(* Logix 5000 project; controller Example_PLC vendor 1 type 14 code 77 rev 19.11; software revision 19.01; part 3 of 6 *)
(* tags used below, declared in another part *)
   ENABLE : BOOL;
(* AKD_Jog, continued *)

ROUTINE Prescan   (* ladder *)
// Prescan
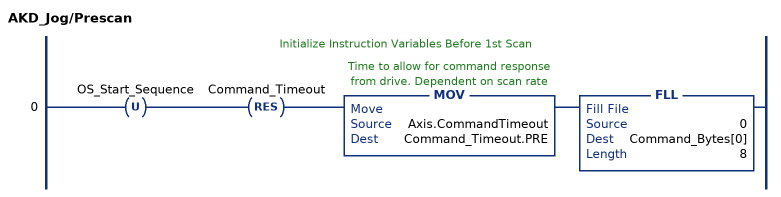
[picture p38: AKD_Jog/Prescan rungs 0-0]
   // Initialize Instruction Variables Before 1st Scan
   0: OTU(OS_Start_Sequence)RES(Command_Timeout)MOV(Axis.CommandTimeout,Command_Timeout.PRE)FLL(0,Command_Bytes[0],8);
END_ROUTINE
END_ADD_ON_INSTRUCTION

ADD_ON_INSTRUCTION AKD_Move   (* revision 3.1, ExecutePrescan, ExecuteEnableInFalse *)
// Motion Axis Move - Position Move
// Revision note:
// Don't error if Command_Timeout preset is 0
VAR_IN_OUT
   Axis : AKD_Axis; {required}
END_VAR
VAR_INPUT
   Move_Type : SINT; {required}   // Move Type (0=Absolute, 1=Incremental)
   Accel : DINT; {required}   // Acceleration
   Decel : DINT; {required}   // Deceleration
   Speed : DINT; {required}   // Move Speed
   Position : DINT; {required}   // Target Position
END_VAR
VAR_OUTPUT
   DN : BOOL; {access Read Only, visible}   // Command Successfully Initiated
   ER : BOOL; {access Read Only, visible}   // Error
   IP : BOOL; {access Read Only, visible}   // Command in Process
   PC : BOOL; {access Read Only, visible}   // Command Process Complete
END_VAR
VAR
   Step : SINT;   // Sequence Step Number
   Command_Axis_Number : SINT;
   Response_Axis_Number : SINT;
   Set_Accel : AKD_Set_Accel;
   Set_Decel : AKD_Set_Decel;
   Set_Velocity : AKD_Set_Velocity;
   OS_Start_Sequence : BOOL;
   Set_Position : AKD_Set_Position;
   Command_Timeout : TIMER := (PRE := 200);
   Command_Bytes : SINT[64];
   ErrorData : SINT[8];
END_VAR

ROUTINE EnableInFalse   (* ladder *)
// EnableIn_False
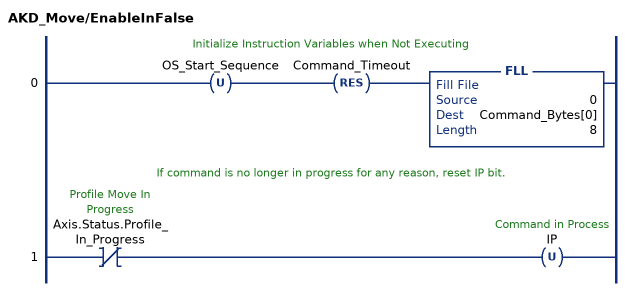
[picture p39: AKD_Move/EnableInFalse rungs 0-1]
   // Initialize Instruction Variables when Not Executing
   0: OTU(OS_Start_Sequence)RES(Command_Timeout)FLL(0,Command_Bytes[0],8);
   // If command is no longer in progress for any reason, reset IP bit.
   1: XIO(Axis.Status.Profile_In_Progress)OTU(IP);
END_ROUTINE

ROUTINE Logic   (* ladder *)
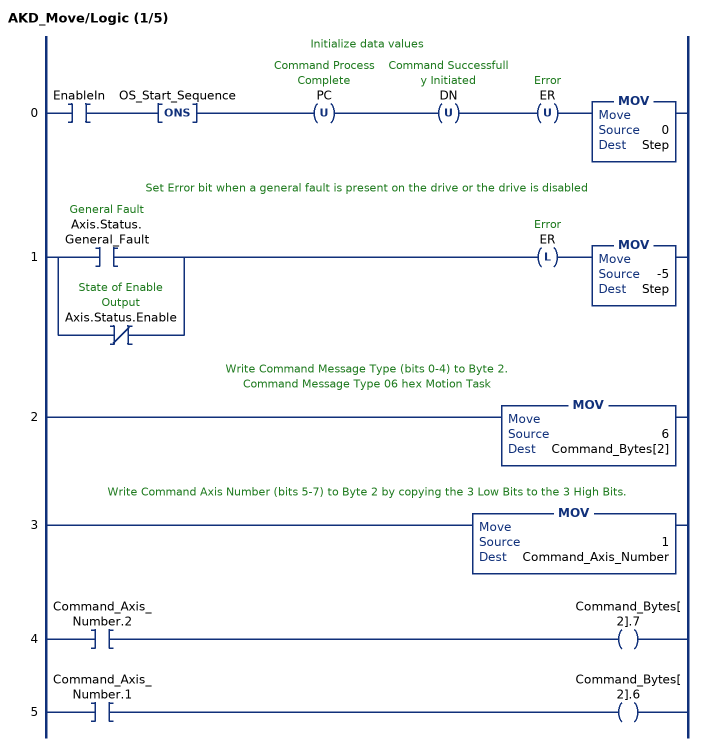
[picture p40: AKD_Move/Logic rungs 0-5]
   // Initialize data values
   0: XIC(EnableIn)ONS(OS_Start_Sequence)OTU(PC)OTU(DN)OTU(ER)MOV(0,Step);
   // Set Error bit when a general fault is present on the drive or the drive is disabled
   1: [XIC(Axis.Status.General_Fault) ,XIO(Axis.Status.Enable) ]OTL(ER)MOV(-5,Step);
   // Write Command Message Type (bits 0-4) to Byte 2.
   // Command Message Type 06 hex Motion Task
   2: MOV(6,Command_Bytes[2]);
   // Write Command Axis Number (bits 5-7) to Byte 2 by copying the 3 Low Bits to the 3 High Bits.
   3: MOV(1,Command_Axis_Number);
   4: XIC(Command_Axis_Number.2)OTE(Command_Bytes[2].7);
   5: XIC(Command_Axis_Number.1)OTE(Command_Bytes[2].6);
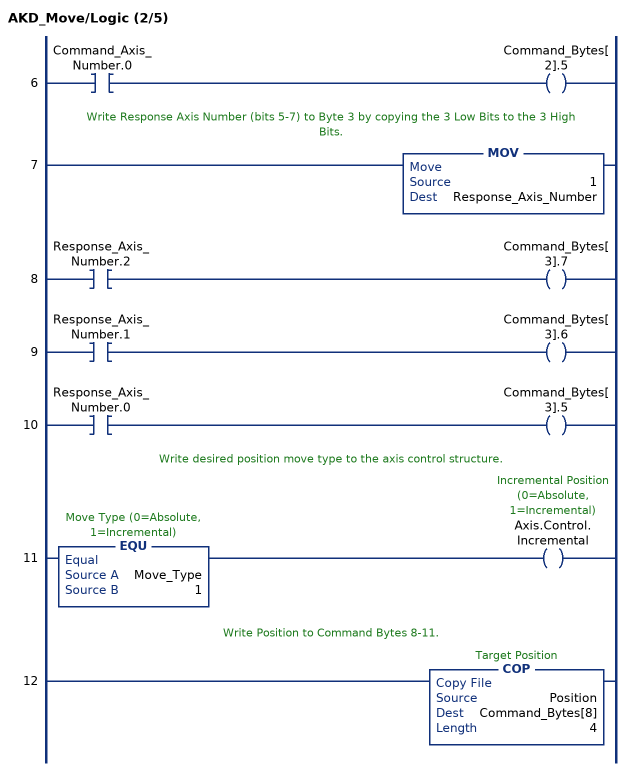
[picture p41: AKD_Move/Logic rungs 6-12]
   6: XIC(Command_Axis_Number.0)OTE(Command_Bytes[2].5);
   // Write Response Axis Number (bits 5-7) to Byte 3 by copying the 3 Low Bits to the 3 High Bits.
   7: MOV(1,Response_Axis_Number);
   8: XIC(Response_Axis_Number.2)OTE(Command_Bytes[3].7);
   9: XIC(Response_Axis_Number.1)OTE(Command_Bytes[3].6);
   10: XIC(Response_Axis_Number.0)OTE(Command_Bytes[3].5);
   // Write desired position move type to the axis control structure.
   11: EQU(Move_Type,1)OTE(Axis.Control.Incremental);
   // Write Position to Command Bytes 8-11.
   12: COP(Position,Command_Bytes[8],4);
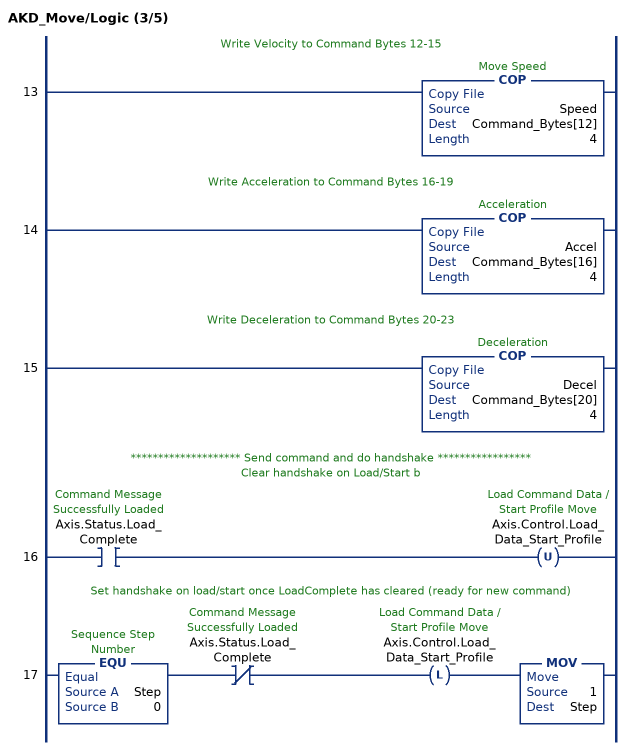
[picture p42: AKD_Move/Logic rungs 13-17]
   // Write Velocity to Command Bytes 12-15
   13: COP(Speed,Command_Bytes[12],4);
   // Write Acceleration to Command Bytes 16-19
   14: COP(Accel,Command_Bytes[16],4);
   // Write Deceleration to Command Bytes 20-23
   15: COP(Decel,Command_Bytes[20],4);
   // ******************** Send command and do handshake *****************
   // Clear handshake on Load/Start b
   16: XIC(Axis.Status.Load_Complete)OTU(Axis.Control.Load_Data_Start_Profile);
   // Set handshake on load/start once LoadComplete has cleared (ready for new command)
   17: EQU(Step,0)XIO(Axis.Status.Load_Complete)OTL(Axis.Control.Load_Data_Start_Profile)MOV(1,Step);
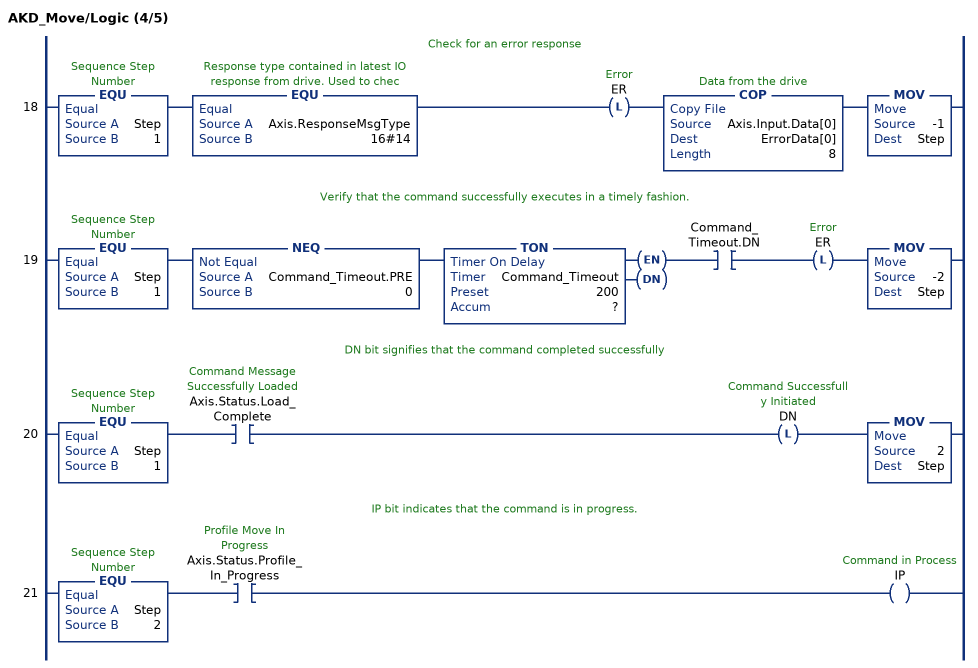
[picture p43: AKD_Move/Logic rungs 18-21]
   // Check for an error response
   18: EQU(Step,1)EQU(Axis.ResponseMsgType,16#14)OTL(ER)COP(Axis.Input.Data[0],ErrorData[0],8)MOV(-1,Step);
   // Verify that the command successfully executes in a timely fashion.
   19: EQU(Step,1)NEQ(Command_Timeout.PRE,0)TON(Command_Timeout,?,?)XIC(Command_Timeout.DN)OTL(ER)MOV(-2,Step);
   // DN bit signifies that the command completed successfully
   20: EQU(Step,1)XIC(Axis.Status.Load_Complete)OTL(DN)MOV(2,Step);
   // IP bit indicates that the command is in progress.
   21: EQU(Step,2)XIC(Axis.Status.Profile_In_Progress)OTE(IP);
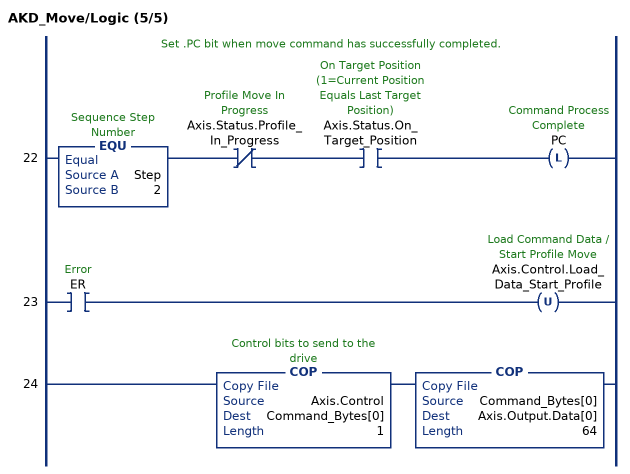
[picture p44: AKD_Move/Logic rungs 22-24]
   // Set .PC bit when move command has successfully completed.
   22: EQU(Step,2)XIO(Axis.Status.Profile_In_Progress)XIC(Axis.Status.On_Target_Position)OTL(PC);
   23: XIC(ER)OTU(Axis.Control.Load_Data_Start_Profile);
   24: COP(Axis.Control,Command_Bytes[0],1)COP(Command_Bytes[0],Axis.Output.Data[0],64);
END_ROUTINE

ROUTINE Prescan   (* ladder *)
// Prescan
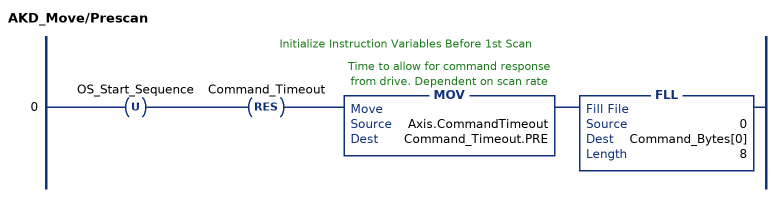
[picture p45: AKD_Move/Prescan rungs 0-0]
   // Initialize Instruction Variables Before 1st Scan
   0: OTU(OS_Start_Sequence)RES(Command_Timeout)MOV(Axis.CommandTimeout,Command_Timeout.PRE)FLL(0,Command_Bytes[0],8);
END_ROUTINE
END_ADD_ON_INSTRUCTION

ADD_ON_INSTRUCTION AKD_Set_Accel   (* revision 2.1, ExecutePrescan, ExecuteEnableInFalse *)
// Set Drive Acceleration
// Revision note:
// Don't error if Command_Timeout preset is 0
VAR_OUTPUT
   DN : BOOL; {access Read Only, visible}   // Command Successful
   ER : BOOL; {access Read Only, visible}   // Error
END_VAR
VAR_IN_OUT
   Axis : AKD_Axis; {required}
END_VAR
VAR_INPUT
   Accel : DINT; {required}   // Acceleration
END_VAR
VAR
   Response_Bytes : SINT[8];
   Accel_Internal : DINT;   // Scaled Accel Value for Drive
   Command_Timeout : TIMER := (PRE := 100);   // Timeout Timer
   Command_Message_Type : SINT;   // Command Message Type
   Command_Axis_Number : SINT;   // Command Axis Number
   Response_Message_Type : SINT;   // Response Message Type
   Response_Axis_Number : SINT;   // Response Axis Number
   Command_Bytes : SINT[8];
   OS_LoadStart : BOOL;
   Step : SINT;
END_VAR

ROUTINE EnableInFalse   (* ladder *)
// EnableIn_False
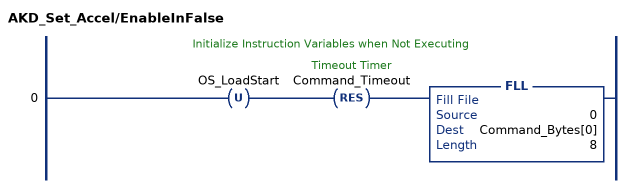
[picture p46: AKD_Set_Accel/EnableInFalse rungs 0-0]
   // Initialize Instruction Variables when Not Executing
   0: OTU(OS_LoadStart)RES(Command_Timeout)FLL(0,Command_Bytes[0],8);
END_ROUTINE

ROUTINE Logic   (* ladder *)
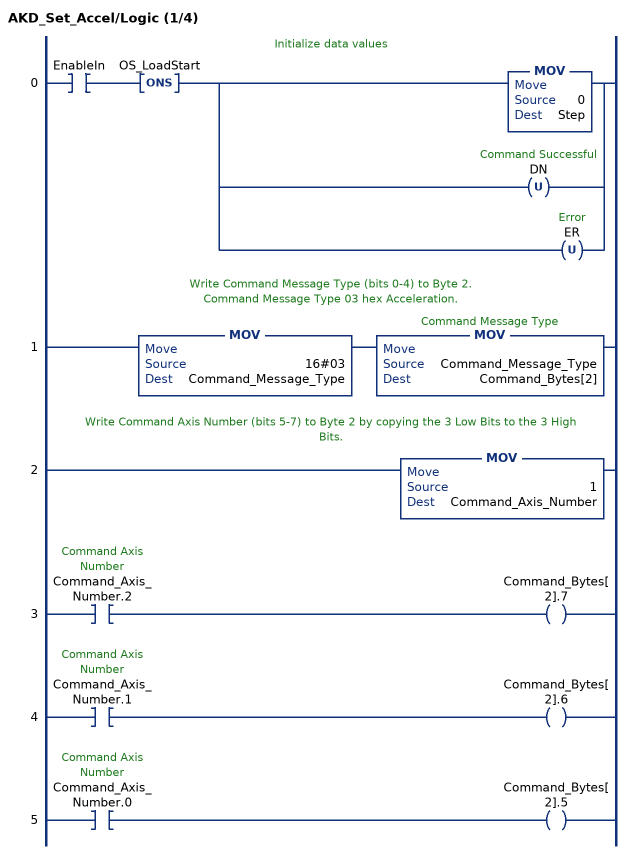
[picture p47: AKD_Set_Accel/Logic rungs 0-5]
   // Initialize data values
   0: XIC(EnableIn)ONS(OS_LoadStart)[MOV(0,Step) ,OTU(DN) ,OTU(ER) ];
   // Write Command Message Type (bits 0-4) to Byte 2.
   // Command Message Type 03 hex Acceleration.
   1: MOV(16#03,Command_Message_Type)MOV(Command_Message_Type,Command_Bytes[2]);
   // Write Command Axis Number (bits 5-7) to Byte 2 by copying the 3 Low Bits to the 3 High Bits.
   2: MOV(1,Command_Axis_Number);
   3: XIC(Command_Axis_Number.2)OTE(Command_Bytes[2].7);
   4: XIC(Command_Axis_Number.1)OTE(Command_Bytes[2].6);
   5: XIC(Command_Axis_Number.0)OTE(Command_Bytes[2].5);
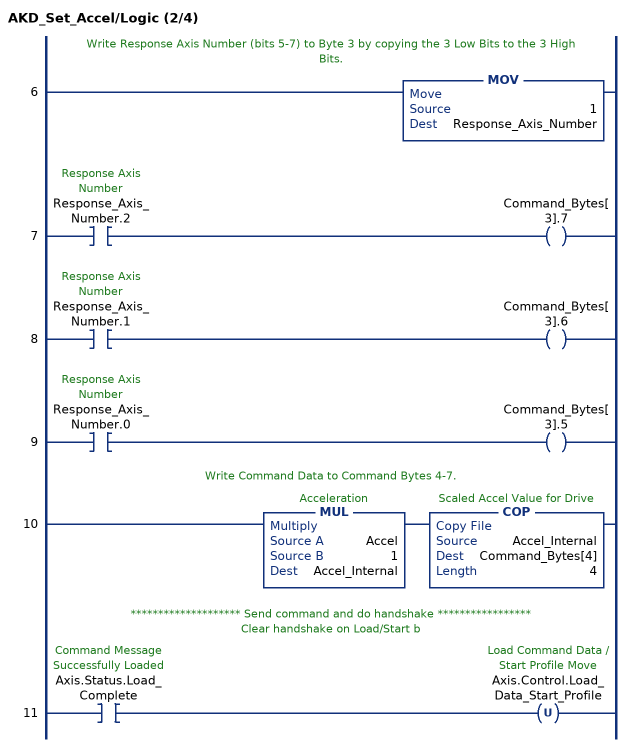
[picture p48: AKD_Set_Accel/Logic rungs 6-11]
   // Write Response Axis Number (bits 5-7) to Byte 3 by copying the 3 Low Bits to the 3 High Bits.
   6: MOV(1,Response_Axis_Number);
   7: XIC(Response_Axis_Number.2)OTE(Command_Bytes[3].7);
   8: XIC(Response_Axis_Number.1)OTE(Command_Bytes[3].6);
   9: XIC(Response_Axis_Number.0)OTE(Command_Bytes[3].5);
   // Write Command Data to Command Bytes 4-7.
   10: MUL(Accel,1,Accel_Internal)COP(Accel_Internal,Command_Bytes[4],4);
   // ******************** Send command and do handshake *****************
   // Clear handshake on Load/Start b
   11: XIC(Axis.Status.Load_Complete)OTU(Axis.Control.Load_Data_Start_Profile);
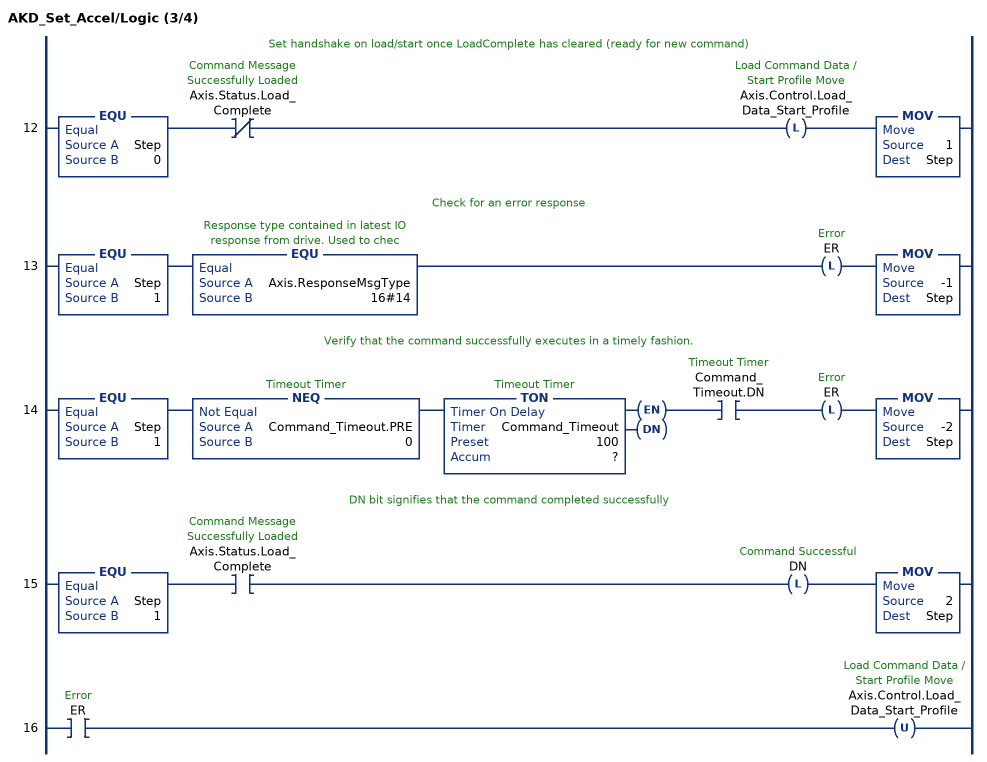
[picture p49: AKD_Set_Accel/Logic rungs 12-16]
   // Set handshake on load/start once LoadComplete has cleared (ready for new command)
   12: EQU(Step,0)XIO(Axis.Status.Load_Complete)OTL(Axis.Control.Load_Data_Start_Profile)MOV(1,Step);
   // Check for an error response
   13: EQU(Step,1)EQU(Axis.ResponseMsgType,16#14)OTL(ER)MOV(-1,Step);
   // Verify that the command successfully executes in a timely fashion.
   14: EQU(Step,1)NEQ(Command_Timeout.PRE,0)TON(Command_Timeout,?,?)XIC(Command_Timeout.DN)OTL(ER)MOV(-2,Step);
   // DN bit signifies that the command completed successfully
   15: EQU(Step,1)XIC(Axis.Status.Load_Complete)OTL(DN)MOV(2,Step);
   16: XIC(ER)OTU(Axis.Control.Load_Data_Start_Profile);
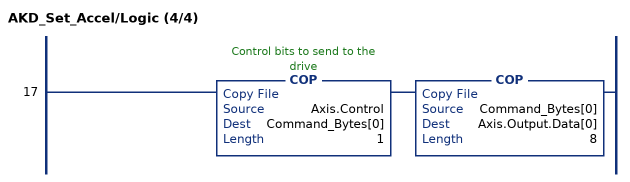
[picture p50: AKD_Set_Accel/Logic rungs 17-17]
   17: COP(Axis.Control,Command_Bytes[0],1)COP(Command_Bytes[0],Axis.Output.Data[0],8);
END_ROUTINE

ROUTINE Prescan   (* ladder *)
// Prescan
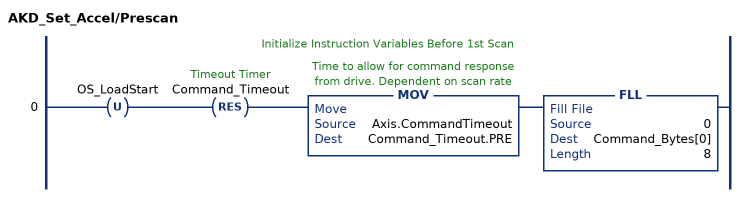
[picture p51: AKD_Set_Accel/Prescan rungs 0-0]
   // Initialize Instruction Variables Before 1st Scan
   0: OTU(OS_LoadStart)RES(Command_Timeout)MOV(Axis.CommandTimeout,Command_Timeout.PRE)FLL(0,Command_Bytes[0],8);
END_ROUTINE
END_ADD_ON_INSTRUCTION

ADD_ON_INSTRUCTION AKD_Set_Attribute   (* revision 2.1, ExecutePrescan, ExecuteEnableInFalse *)
// Set Position Controller Attribute
// Revision note:
// Don't error if Command_Timeout preset is 0
VAR_OUTPUT
   DN : BOOL; {access Read Only, visible}   // Command Successful
   ER : BOOL; {access Read Only, visible}   // Error
END_VAR
VAR_IN_OUT
   Axis : AKD_Axis; {required}
END_VAR
VAR_INPUT
   Attribute_Number : INT; {visible}   // Attribute Number (see help for options)
   Attribute_Value : DINT; {required}   // Attribute Value
END_VAR
VAR
   Command_Timeout : TIMER := (PRE := 200);   // Timeout Timer
   Command_Message_Type : SINT;   // Command Message Type
   Command_Axis_Number : SINT;   // Command Axis Number
   Step : SINT;
   Command_Bytes : SINT[8];
   OS_LoadStart : BOOL;
END_VAR

ROUTINE EnableInFalse   (* ladder *)
// EnableIn_False
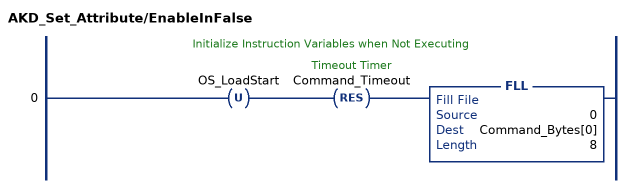
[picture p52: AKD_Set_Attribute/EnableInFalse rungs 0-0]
   // Initialize Instruction Variables when Not Executing
   0: OTU(OS_LoadStart)RES(Command_Timeout)FLL(0,Command_Bytes[0],8);
END_ROUTINE

ROUTINE Logic   (* ladder *)
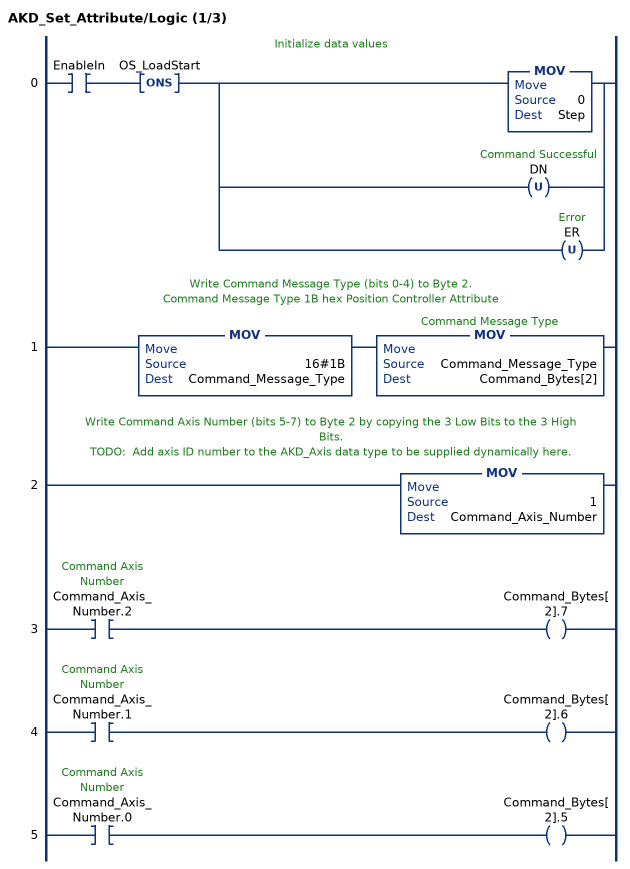
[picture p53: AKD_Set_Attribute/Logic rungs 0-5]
   // Initialize data values
   0: XIC(EnableIn)ONS(OS_LoadStart)[MOV(0,Step) ,OTU(DN) ,OTU(ER) ];
   // Write Command Message Type (bits 0-4) to Byte 2.
   // Command Message Type 1B hex Position Controller Attribute
   1: MOV(16#1B,Command_Message_Type)MOV(Command_Message_Type,Command_Bytes[2]);
   // Write Command Axis Number (bits 5-7) to Byte 2 by copying the 3 Low Bits to the 3 High Bits.
   // TODO:  Add axis ID number to the AKD_Axis data type to be supplied dynamically here.
   2: MOV(1,Command_Axis_Number);
   3: XIC(Command_Axis_Number.2)OTE(Command_Bytes[2].7);
   4: XIC(Command_Axis_Number.1)OTE(Command_Bytes[2].6);
   5: XIC(Command_Axis_Number.0)OTE(Command_Bytes[2].5);
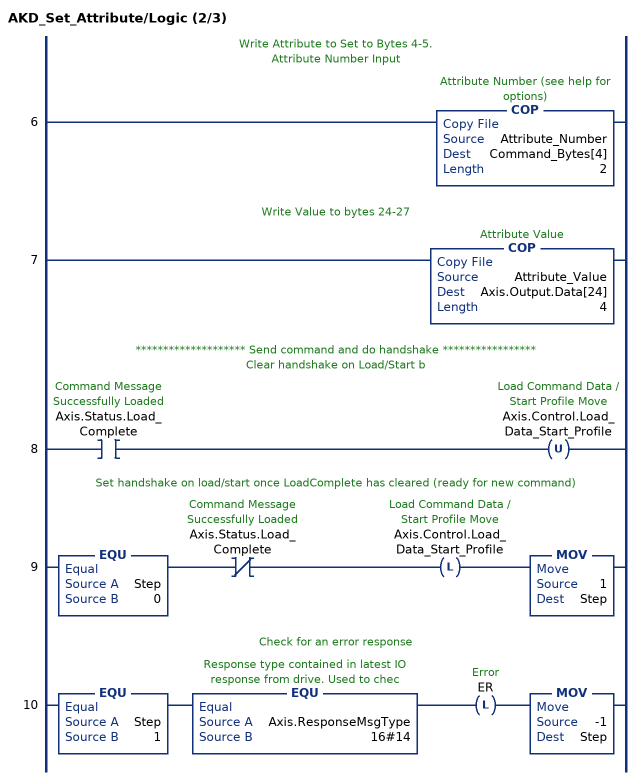
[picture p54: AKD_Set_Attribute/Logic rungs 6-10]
   // Write Attribute to Set to Bytes 4-5.
   // Attribute Number Input
   6: COP(Attribute_Number,Command_Bytes[4],2);
   // Write Value to bytes 24-27
   7: COP(Attribute_Value,Axis.Output.Data[24],4);
   // ******************** Send command and do handshake *****************
   // Clear handshake on Load/Start b
   8: XIC(Axis.Status.Load_Complete)OTU(Axis.Control.Load_Data_Start_Profile);
   // Set handshake on load/start once LoadComplete has cleared (ready for new command)
   9: EQU(Step,0)XIO(Axis.Status.Load_Complete)OTL(Axis.Control.Load_Data_Start_Profile)MOV(1,Step);
   // Check for an error response
   10: EQU(Step,1)EQU(Axis.ResponseMsgType,16#14)OTL(ER)MOV(-1,Step);
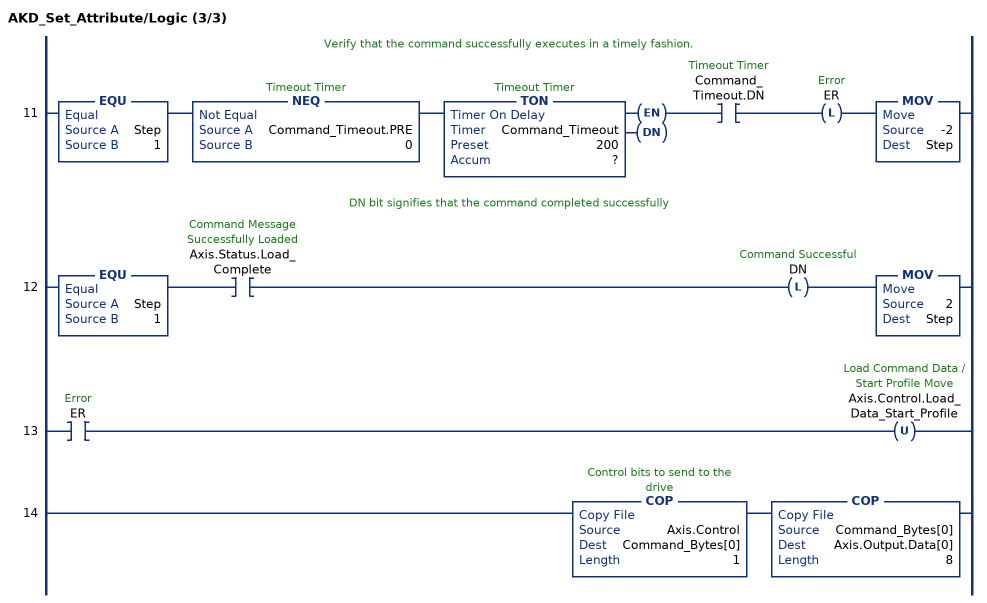
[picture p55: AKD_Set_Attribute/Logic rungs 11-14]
   // Verify that the command successfully executes in a timely fashion.
   11: EQU(Step,1)NEQ(Command_Timeout.PRE,0)TON(Command_Timeout,?,?)XIC(Command_Timeout.DN)OTL(ER)MOV(-2,Step);
   // DN bit signifies that the command completed successfully
   12: EQU(Step,1)XIC(Axis.Status.Load_Complete)OTL(DN)MOV(2,Step);
   13: XIC(ER)OTU(Axis.Control.Load_Data_Start_Profile);
   14: COP(Axis.Control,Command_Bytes[0],1)COP(Command_Bytes[0],Axis.Output.Data[0],8);
END_ROUTINE
(* Logix 5000 project; controller Example_PLC vendor 1 type 14 code 77 rev 19.11; software revision 19.01; part 6 of 6 *)

ADD_ON_INSTRUCTION AKD_Set_Velocity   (* revision 2.1, ExecutePrescan, ExecuteEnableInFalse *)
// Set Drive Velocity
// Revision note:
// Don't error if Command_Timeout preset is 0
VAR_OUTPUT
   DN : BOOL; {access Read Only, visible}   // Command Successful
   ER : BOOL; {access Read Only, visible}   // Error
END_VAR
VAR_IN_OUT
   Axis : AKD_Axis; {required}
END_VAR
VAR_INPUT
   Velocity : DINT; {required}   // Velocity
END_VAR
VAR
   Response_Bytes : SINT[8];
   OS_LoadStart : BOOL;
   Velocity_Internal : DINT;   // Scaled Velocity Value for Drive
   Command_Timeout : TIMER := (PRE := 100);   // Timeout Timer
   Command_Message_Type : SINT;   // Command Message Type
   Command_Axis_Number : SINT;   // Command Axis Number
   Response_Message_Type : SINT;   // Response Message Type
   Response_Axis_Number : SINT;   // Response Axis Number
   Command_Bytes : SINT[8];
   Step : SINT;
END_VAR

ROUTINE EnableInFalse   (* ladder *)
// EnableIn_False
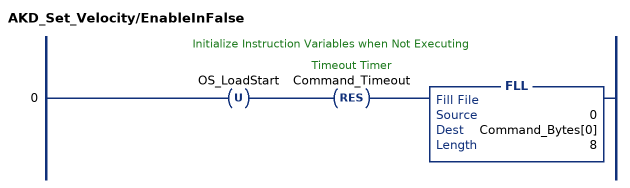
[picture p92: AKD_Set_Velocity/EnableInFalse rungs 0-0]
   // Initialize Instruction Variables when Not Executing
   0: OTU(OS_LoadStart)RES(Command_Timeout)FLL(0,Command_Bytes[0],8);
END_ROUTINE

ROUTINE Logic   (* ladder *)
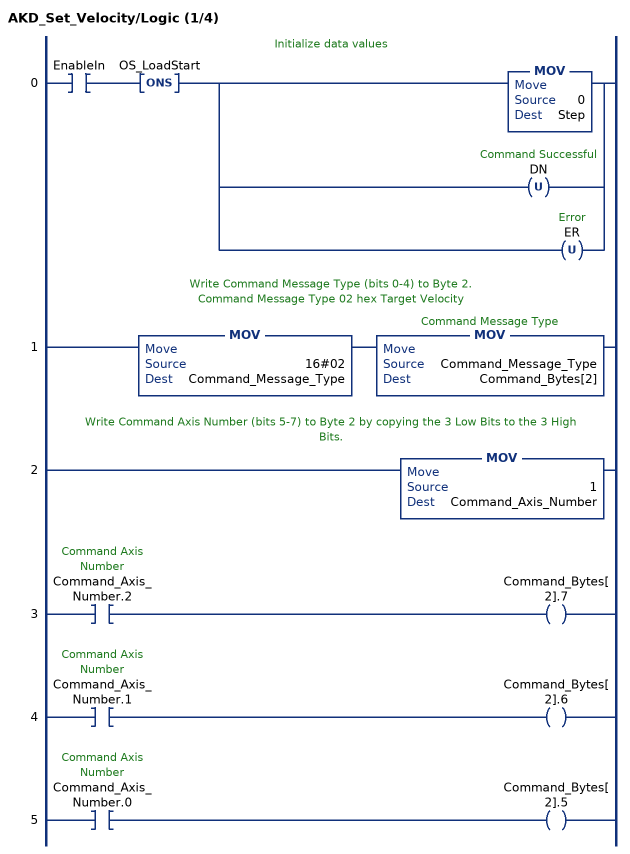
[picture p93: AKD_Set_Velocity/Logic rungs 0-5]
   // Initialize data values
   0: XIC(EnableIn)ONS(OS_LoadStart)[MOV(0,Step) ,OTU(DN) ,OTU(ER) ];
   // Write Command Message Type (bits 0-4) to Byte 2.
   // Command Message Type 02 hex Target Velocity
   1: MOV(16#02,Command_Message_Type)MOV(Command_Message_Type,Command_Bytes[2]);
   // Write Command Axis Number (bits 5-7) to Byte 2 by copying the 3 Low Bits to the 3 High Bits.
   2: MOV(1,Command_Axis_Number);
   3: XIC(Command_Axis_Number.2)OTE(Command_Bytes[2].7);
   4: XIC(Command_Axis_Number.1)OTE(Command_Bytes[2].6);
   5: XIC(Command_Axis_Number.0)OTE(Command_Bytes[2].5);
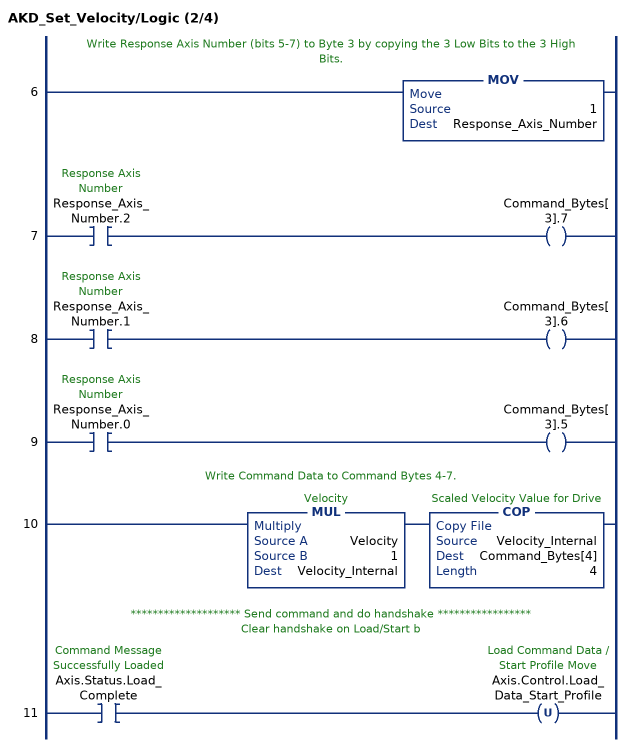
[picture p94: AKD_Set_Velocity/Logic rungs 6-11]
   // Write Response Axis Number (bits 5-7) to Byte 3 by copying the 3 Low Bits to the 3 High Bits.
   6: MOV(1,Response_Axis_Number);
   7: XIC(Response_Axis_Number.2)OTE(Command_Bytes[3].7);
   8: XIC(Response_Axis_Number.1)OTE(Command_Bytes[3].6);
   9: XIC(Response_Axis_Number.0)OTE(Command_Bytes[3].5);
   // Write Command Data to Command Bytes 4-7.
   10: MUL(Velocity,1,Velocity_Internal)COP(Velocity_Internal,Command_Bytes[4],4);
   // ******************** Send command and do handshake *****************
   // Clear handshake on Load/Start b
   11: XIC(Axis.Status.Load_Complete)OTU(Axis.Control.Load_Data_Start_Profile);
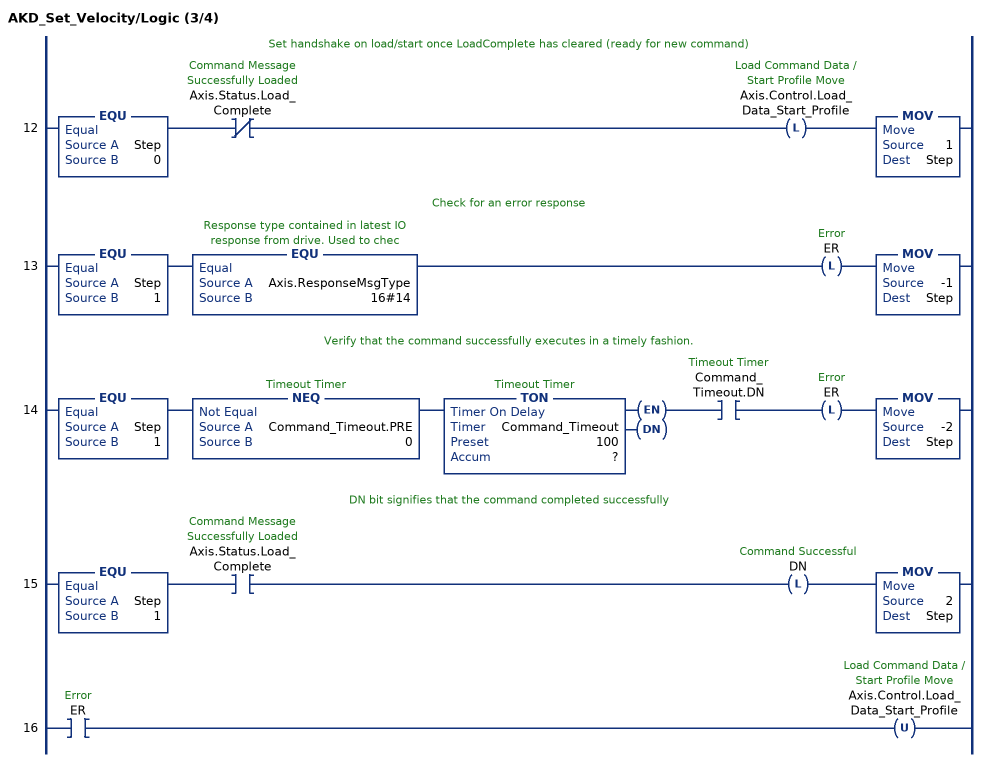
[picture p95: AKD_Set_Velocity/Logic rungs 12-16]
   // Set handshake on load/start once LoadComplete has cleared (ready for new command)
   12: EQU(Step,0)XIO(Axis.Status.Load_Complete)OTL(Axis.Control.Load_Data_Start_Profile)MOV(1,Step);
   // Check for an error response
   13: EQU(Step,1)EQU(Axis.ResponseMsgType,16#14)OTL(ER)MOV(-1,Step);
   // Verify that the command successfully executes in a timely fashion.
   14: EQU(Step,1)NEQ(Command_Timeout.PRE,0)TON(Command_Timeout,?,?)XIC(Command_Timeout.DN)OTL(ER)MOV(-2,Step);
   // DN bit signifies that the command completed successfully
   15: EQU(Step,1)XIC(Axis.Status.Load_Complete)OTL(DN)MOV(2,Step);
   16: XIC(ER)OTU(Axis.Control.Load_Data_Start_Profile);
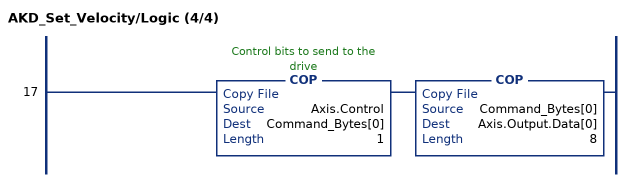
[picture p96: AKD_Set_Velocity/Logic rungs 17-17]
   17: COP(Axis.Control,Command_Bytes[0],1)COP(Command_Bytes[0],Axis.Output.Data[0],8);
END_ROUTINE

ROUTINE Prescan   (* ladder *)
// Prescan
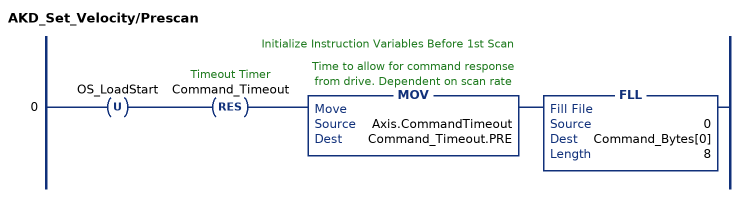
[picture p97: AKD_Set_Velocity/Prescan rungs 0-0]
   // Initialize Instruction Variables Before 1st Scan
   0: OTU(OS_LoadStart)RES(Command_Timeout)MOV(Axis.CommandTimeout,Command_Timeout.PRE)FLL(0,Command_Bytes[0],8);
END_ROUTINE
END_ADD_ON_INSTRUCTION

ADD_ON_INSTRUCTION AKD_Shutdown   (* revision 2.0, ExecutePrescan, ExecuteEnableInFalse *)
// Motion Hard Stop
VAR_OUTPUT
   DN : BOOL; {access Read Only, visible}   // Command Successful
   ER : BOOL; {access Read Only, visible}   // Error
END_VAR
VAR_IN_OUT
   Axis : AKD_Axis; {required}
END_VAR
VAR
   Command_Timeout : TIMER := (PRE := 2000);   // Timeout Timer
END_VAR

ROUTINE EnableInFalse   (* ladder *)
// Enable In False
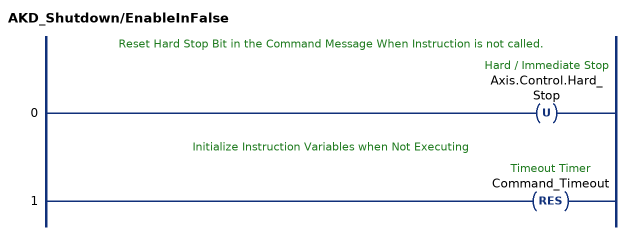
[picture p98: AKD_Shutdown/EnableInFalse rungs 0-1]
   // Reset Hard Stop Bit in the Command Message When Instruction is not called.
   0: OTU(Axis.Control.Hard_Stop);
   // Initialize Instruction Variables when Not Executing
   1: RES(Command_Timeout);
END_ROUTINE

ROUTINE Logic   (* ladder *)
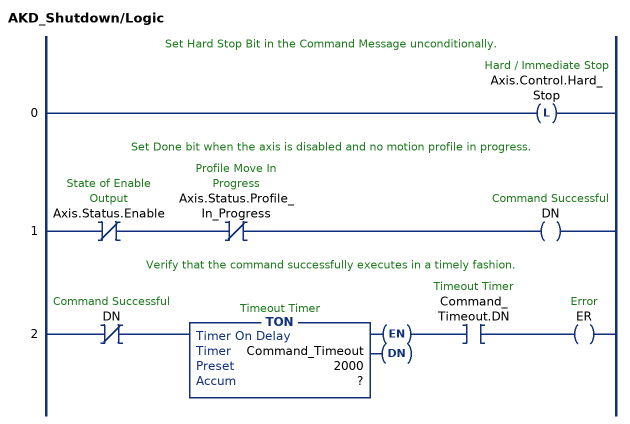
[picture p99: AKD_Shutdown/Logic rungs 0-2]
   // Set Hard Stop Bit in the Command Message unconditionally.
   0: OTL(Axis.Control.Hard_Stop);
   // Set Done bit when the axis is disabled and no motion profile in progress.
   1: XIO(Axis.Status.Enable)XIO(Axis.Status.Profile_In_Progress)OTE(DN);
   // Verify that the command successfully executes in a timely fashion.
   2: XIO(DN)TON(Command_Timeout,?,?)XIC(Command_Timeout.DN)OTE(ER);
END_ROUTINE

ROUTINE Prescan   (* ladder *)
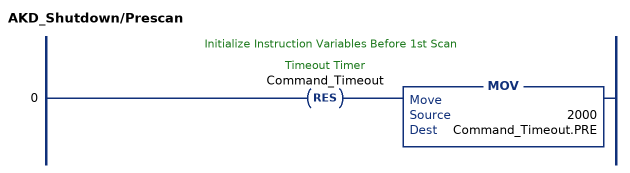
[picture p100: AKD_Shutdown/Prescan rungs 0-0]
   // Initialize Instruction Variables Before 1st Scan
   0: RES(Command_Timeout)MOV(2000,Command_Timeout.PRE);
END_ROUTINE
END_ADD_ON_INSTRUCTION

ADD_ON_INSTRUCTION AKD_Stop_Smooth   (* revision 2.3, ExecutePrescan, ExecuteEnableInFalse *)
// Motion Smooth Stop
// Revision note:
// Remove the command timeout (allow unlimited time to stop). Add an IP In Progress bit which is active while stopping.
VAR_OUTPUT
   DN : BOOL; {access Read Only, visible}   // Command Successful
   ER : BOOL; {access Read Only, visible}   // Error
END_VAR
VAR_IN_OUT
   Axis : AKD_Axis; {required}
END_VAR
VAR_OUTPUT
   IP : BOOL; {access Read Only, visible}   // In Progress
END_VAR

ROUTINE EnableInFalse   (* ladder *)
// Enable In False
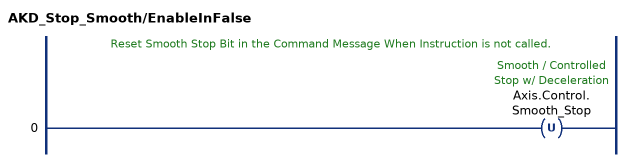
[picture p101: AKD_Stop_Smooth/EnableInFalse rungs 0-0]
   // Reset Smooth Stop Bit in the Command Message When Instruction is not called.
   0: OTU(Axis.Control.Smooth_Stop);
END_ROUTINE

ROUTINE Logic   (* ladder *)
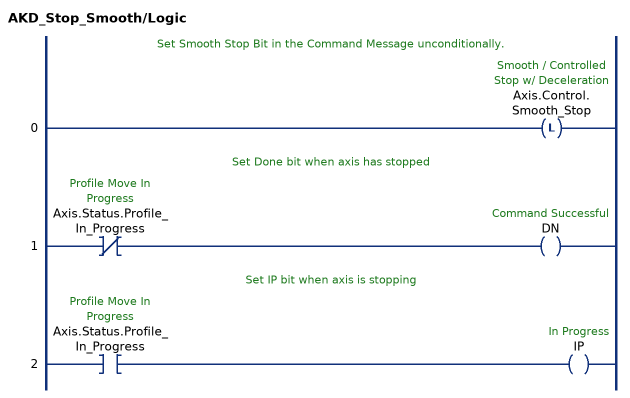
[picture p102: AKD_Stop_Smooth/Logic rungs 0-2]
   // Set Smooth Stop Bit in the Command Message unconditionally.
   0: OTL(Axis.Control.Smooth_Stop);
   // Set Done bit when axis has stopped
   1: XIO(Axis.Status.Profile_In_Progress)OTE(DN);
   // Set IP bit when axis is stopping
   2: XIC(Axis.Status.Profile_In_Progress)OTE(IP);
END_ROUTINE

ROUTINE Prescan   (* ladder *)
END_ROUTINE
END_ADD_ON_INSTRUCTION

ADD_ON_INSTRUCTION AKD_Torque_Move   (* revision 2.1, ExecutePrescan, ExecuteEnableInFalse *)
// Set Torque Command
VAR_OUTPUT
   DN : BOOL; {access Read Only, visible}   // Command Successful
   ER : BOOL; {access Read Only, visible}   // Error
END_VAR
VAR_IN_OUT
   Axis : AKD_Axis; {required}
END_VAR
VAR_INPUT
   Torque : DINT; {required}   // Torque Command
END_VAR
VAR
   Response_Bytes : SINT[8];
   OS_LoadStart : BOOL;
   Command_Timeout : TIMER := (PRE := 100);   // Timeout Timer
   Command_Message_Type : SINT;   // Command Message Type
   Command_Axis_Number : SINT;   // Command Axis Number
   Response_Message_Type : SINT;   // Response Message Type
   Response_Axis_Number : SINT;   // Response Axis Number
   Command_Bytes : SINT[8];
   Step : SINT;
END_VAR

ROUTINE EnableInFalse   (* ladder *)
// EnableIn_False
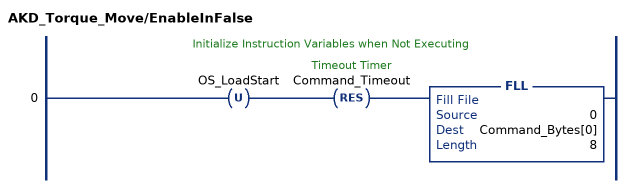
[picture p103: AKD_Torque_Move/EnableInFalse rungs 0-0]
   // Initialize Instruction Variables when Not Executing
   0: OTU(OS_LoadStart)RES(Command_Timeout)FLL(0,Command_Bytes[0],8);
END_ROUTINE

ROUTINE Logic   (* ladder *)
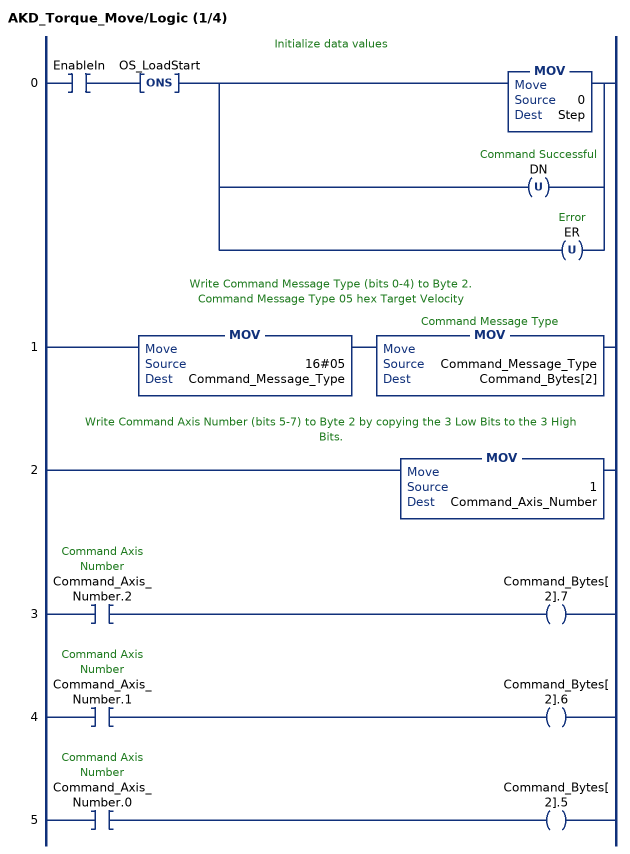
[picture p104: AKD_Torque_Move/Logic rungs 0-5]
   // Initialize data values
   0: XIC(EnableIn)ONS(OS_LoadStart)[MOV(0,Step) ,OTU(DN) ,OTU(ER) ];
   // Write Command Message Type (bits 0-4) to Byte 2.
   // Command Message Type 05 hex Target Velocity
   1: MOV(16#05,Command_Message_Type)MOV(Command_Message_Type,Command_Bytes[2]);
   // Write Command Axis Number (bits 5-7) to Byte 2 by copying the 3 Low Bits to the 3 High Bits.
   2: MOV(1,Command_Axis_Number);
   3: XIC(Command_Axis_Number.2)OTE(Command_Bytes[2].7);
   4: XIC(Command_Axis_Number.1)OTE(Command_Bytes[2].6);
   5: XIC(Command_Axis_Number.0)OTE(Command_Bytes[2].5);
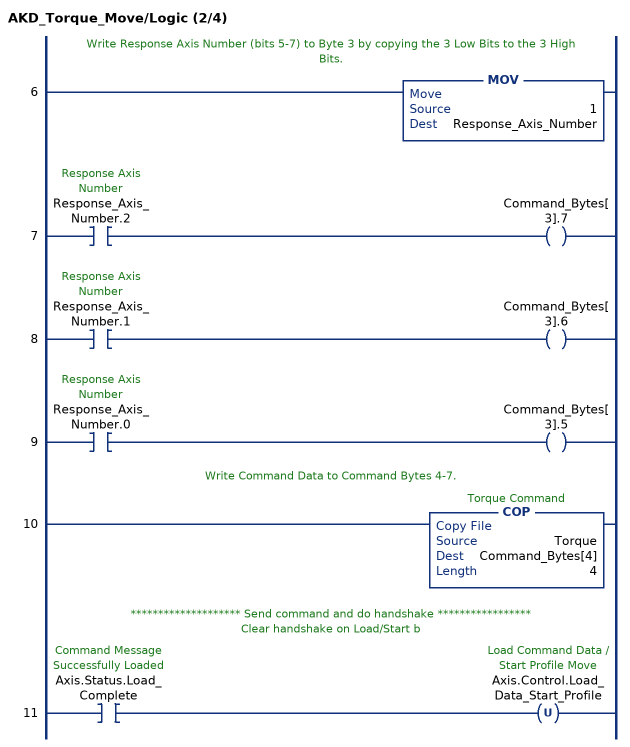
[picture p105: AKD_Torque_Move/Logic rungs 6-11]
   // Write Response Axis Number (bits 5-7) to Byte 3 by copying the 3 Low Bits to the 3 High Bits.
   6: MOV(1,Response_Axis_Number);
   7: XIC(Response_Axis_Number.2)OTE(Command_Bytes[3].7);
   8: XIC(Response_Axis_Number.1)OTE(Command_Bytes[3].6);
   9: XIC(Response_Axis_Number.0)OTE(Command_Bytes[3].5);
   // Write Command Data to Command Bytes 4-7.
   10: COP(Torque,Command_Bytes[4],4);
   // ******************** Send command and do handshake *****************
   // Clear handshake on Load/Start b
   11: XIC(Axis.Status.Load_Complete)OTU(Axis.Control.Load_Data_Start_Profile);
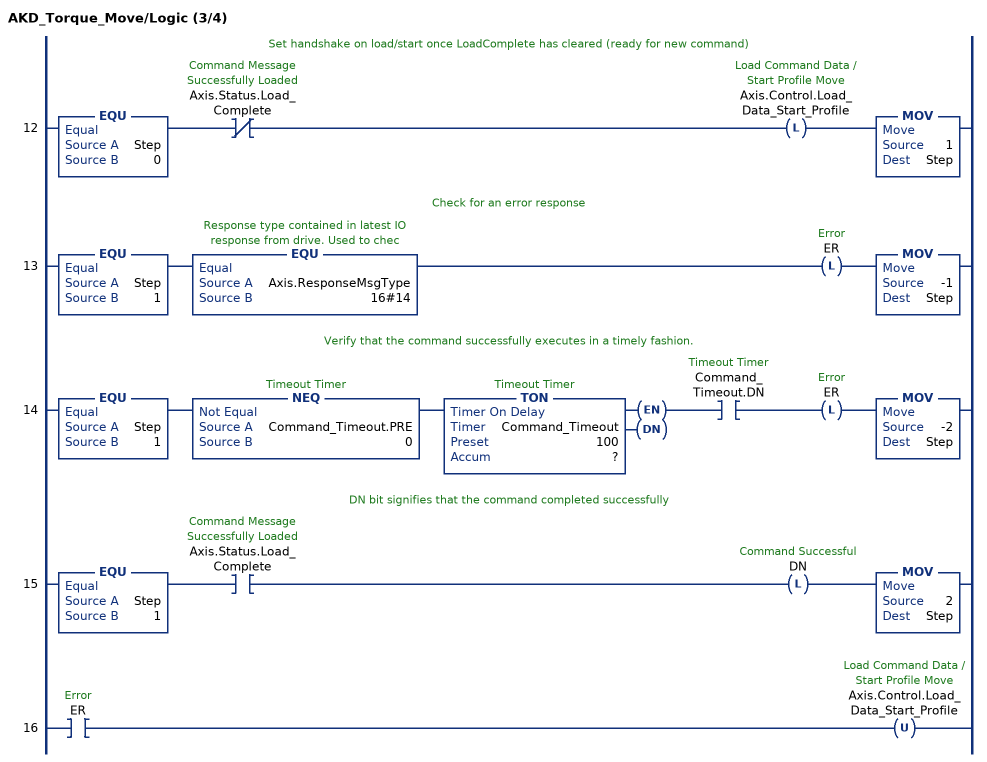
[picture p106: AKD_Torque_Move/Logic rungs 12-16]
   // Set handshake on load/start once LoadComplete has cleared (ready for new command)
   12: EQU(Step,0)XIO(Axis.Status.Load_Complete)OTL(Axis.Control.Load_Data_Start_Profile)MOV(1,Step);
   // Check for an error response
   13: EQU(Step,1)EQU(Axis.ResponseMsgType,16#14)OTL(ER)MOV(-1,Step);
   // Verify that the command successfully executes in a timely fashion.
   14: EQU(Step,1)NEQ(Command_Timeout.PRE,0)TON(Command_Timeout,?,?)XIC(Command_Timeout.DN)OTL(ER)MOV(-2,Step);
   // DN bit signifies that the command completed successfully
   15: EQU(Step,1)XIC(Axis.Status.Load_Complete)OTL(DN)MOV(2,Step);
   16: XIC(ER)OTU(Axis.Control.Load_Data_Start_Profile);
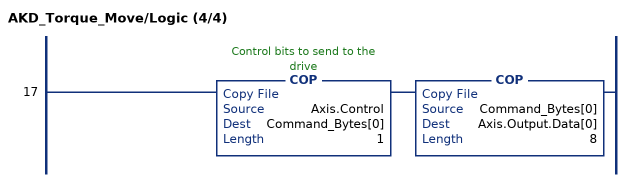
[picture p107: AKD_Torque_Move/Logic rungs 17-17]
   17: COP(Axis.Control,Command_Bytes[0],1)COP(Command_Bytes[0],Axis.Output.Data[0],8);
END_ROUTINE

ROUTINE Prescan   (* ladder *)
// Prescan
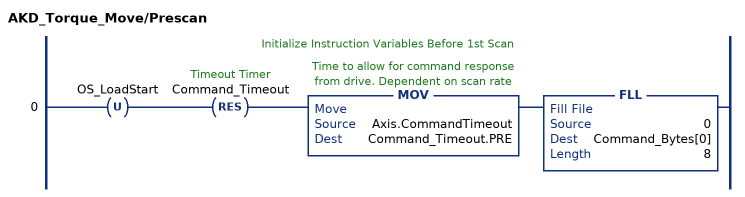
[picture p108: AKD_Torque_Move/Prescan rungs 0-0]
   // Initialize Instruction Variables Before 1st Scan
   0: OTU(OS_LoadStart)RES(Command_Timeout)MOV(Axis.CommandTimeout,Command_Timeout.PRE)FLL(0,Command_Bytes[0],8);
END_ROUTINE
END_ADD_ON_INSTRUCTION

VAR_GLOBAL   (* controller tags *)
   AKD_1 : AKD_Drive;
   Axis_1 : AKD_Drive;
   Axis_1_Dis : AKD_Disable;
   Axis_1_EN : AKD_Enable;
   Axis_1_HOME : AKD_Home;
   Axis_1_Move : AKD_Move;
   AXIS_ONE : AKD_Axis;
   B_DRV_ACTIVE : AKD_Get_Parameter;
   BLK_DRV_DISSOURCE : AKD_Get_Parameter := (Parameter_Number := 121);
   BLK_DRV_MOTIONSTAT : AKD_Get_Parameter := (Parameter_Number := 135);
   BLK_FAULT_RESET : AKD_Fault_Reset;
   BLK_GET_FAULT1 : AKD_Get_Parameter := (Parameter_Number := 478);
   BLK_GET_FAULT10 : AKD_Get_Parameter := (Parameter_Number := 487);
   BLK_GET_FAULT2 : AKD_Get_Parameter := (Parameter_Number := 479);
   BLK_GET_FAULT3 : AKD_Get_Parameter := (Parameter_Number := 480);
   BLK_GET_FAULT4 : AKD_Get_Parameter := (Parameter_Number := 481);
   BLK_GET_FAULT5 : AKD_Get_Parameter := (Parameter_Number := 482);
   BLK_GET_FAULT6 : AKD_Get_Parameter := (Parameter_Number := 483);
   BLK_GET_FAULT7 : AKD_Get_Parameter := (Parameter_Number := 484);
   BLK_GET_FAULT8 : AKD_Get_Parameter := (Parameter_Number := 485);
   BLK_GET_FAULT9 : AKD_Get_Parameter := (Parameter_Number := 486);
   BLK_JOG : AKD_Jog;
   BLK_STOP : AKD_Stop_Smooth;
   CLRFAULT_1_SHOT : BOOL;
   DATA_DRV_DISSOURCE : DINT;
   DATA_DRV_MOTIONSTAT : DINT;
   DISABLE : BOOL;
   DISABLE_1_SHOT : BOOL;
   DISSOURCE_1_SHOT : BOOL;
   ENABLE : BOOL;
   ENABLE_1_SHOT : BOOL;
   FAULT_1 : DINT;
   FAULT_10 : DINT;
   FAULT_2 : DINT;
   FAULT_3 : DINT;
   FAULT_4 : DINT;
   FAULT_5 : DINT;
   FAULT_6 : DINT;
   FAULT_7 : DINT;
   FAULT_8 : DINT;
   FAULT_9 : DINT;
   FAULT_FIRST_STEP : BOOL;
   FB1_Offset_LSB_Data : DINT;
   FB1_Offset_MSB_Data : DINT;
   FB1_Offset_Zero : AKD_Set_Parameter_LINT := (Parameter_Number := 146);
   GET_FAULT_BUSY : BOOL;
   GET_FAULT_COUNTER : DINT;
   GETFAULT_1_SHOT : BOOL;
   HOME_1_SHOT : BOOL;
   JOG_1_SHOT : BOOL;
   JOG_AXIS_1 : BOOL;
   MOTIONSTAT_1_SHOT : BOOL;
   MOVE_1_SHOT : BOOL;
   New_Offset_Data_LSB : DINT;
   New_Offset_Data_MSB : DINT;
   Offset_State_Counter : DINT;
   Read_FB : AKD_Get_Parameter_LINT := (Parameter_Number := 295);
   Start_1SHT : BOOL;
   START_DRV_CLRFAULTS : BOOL;
   START_DRV_DISSOURCE : BOOL;
   START_DRV_MOTIONSTAT : BOOL;
   START_GET_FAULTS : BOOL;
   START_HOME_MOVE : BOOL;
   START_MOVE : BOOL;
   Start_Zero_Routine : BOOL;
   Step1_1SHT : BOOL;
   STOP_1_STOP : BOOL;
   Write_Net_Offset : AKD_Set_Parameter_LINT := (Parameter_Number := 146);
END_VAR

PROGRAM MainProgram   (* main routine MainRoutine *)

ROUTINE MainRoutine   (* ladder *)
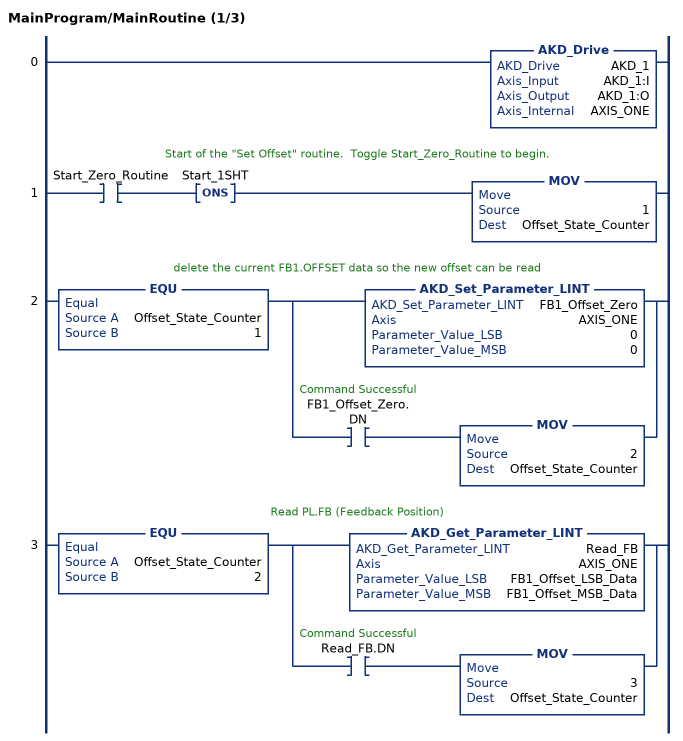
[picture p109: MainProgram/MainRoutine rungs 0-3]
   0: AKD_Drive(AKD_1,AKD_1:I,AKD_1:O,AXIS_ONE);
   // Start of the "Set Offset" routine.  Toggle Start_Zero_Routine to begin.
   1: XIC(Start_Zero_Routine)ONS(Start_1SHT)MOV(1,Offset_State_Counter);
   // delete the current FB1.OFFSET data so the new offset can be read
   2: EQU(Offset_State_Counter,1)[AKD_Set_Parameter_LINT(FB1_Offset_Zero,AXIS_ONE,0,0) ,XIC(FB1_Offset_Zero.DN) MOV(2,Offset_State_Counter) ];
   // Read PL.FB (Feedback Position)
   3: EQU(Offset_State_Counter,2)[AKD_Get_Parameter_LINT(Read_FB,AXIS_ONE,FB1_Offset_LSB_Data,FB1_Offset_MSB_Data) ,XIC(Read_FB.DN) MOV(3,Offset_State_Counter) ];
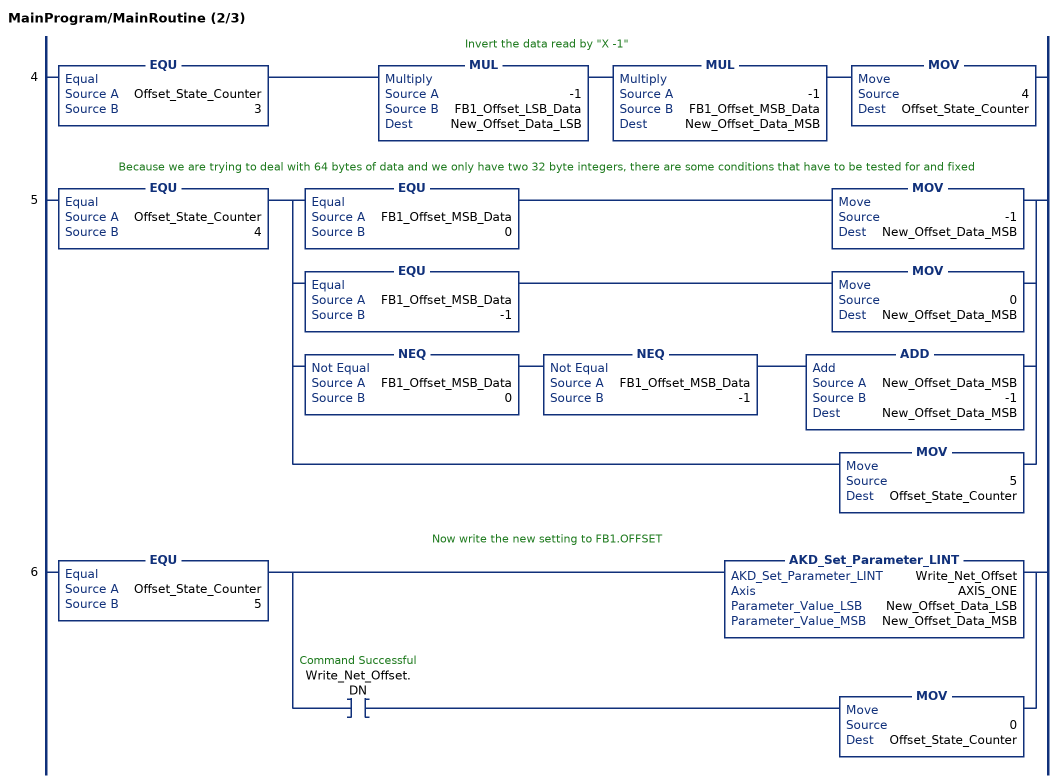
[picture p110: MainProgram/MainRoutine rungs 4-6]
   // Invert the data read by "X -1"
   4: EQU(Offset_State_Counter,3)MUL(-1,FB1_Offset_LSB_Data,New_Offset_Data_LSB)MUL(-1,FB1_Offset_MSB_Data,New_Offset_Data_MSB)MOV(4,Offset_State_Counter);
   // Because we are trying to deal with 64 bytes of data and we only have two 32 byte integers, there are some conditions that have to be tested for and fixed
   5: EQU(Offset_State_Counter,4)[EQU(FB1_Offset_MSB_Data,0) MOV(-1,New_Offset_Data_MSB) ,EQU(FB1_Offset_MSB_Data,-1) MOV(0,New_Offset_Data_MSB) ,NEQ(FB1_Offset_MSB_Data,0) NEQ(FB1_Offset_MSB_Data,-1) ADD(New_Offset_Data_MSB,-1,New_Offset_Data_MSB) ,MOV(5,Offset_State_Counter) ];
   // Now write the new setting to FB1.OFFSET
   6: EQU(Offset_State_Counter,5)[AKD_Set_Parameter_LINT(Write_Net_Offset,AXIS_ONE,New_Offset_Data_LSB,New_Offset_Data_MSB) ,XIC(Write_Net_Offset.DN) MOV(0,Offset_State_Counter) ];
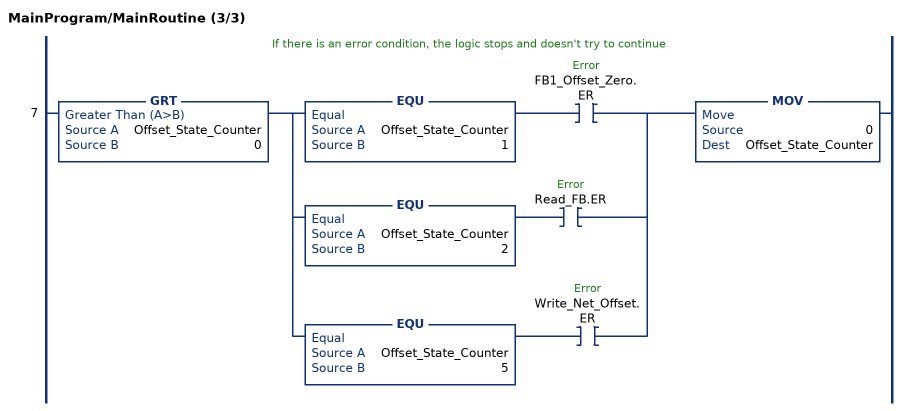
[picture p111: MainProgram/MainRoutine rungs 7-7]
   // If there is an error condition, the logic stops and doesn't try to continue
   7: GRT(Offset_State_Counter,0)[EQU(Offset_State_Counter,1) XIC(FB1_Offset_Zero.ER) ,EQU(Offset_State_Counter,2) XIC(Read_FB.ER) ,EQU(Offset_State_Counter,5) XIC(Write_Net_Offset.ER) ]MOV(0,Offset_State_Counter);
END_ROUTINE
END_PROGRAM
